One B-rep face of a CAD part: STEP entity #1352.
In plain terms, the planar face has unit normal (1, 0, 0).
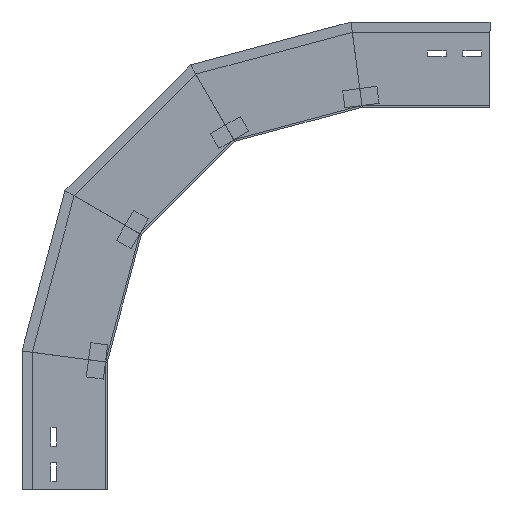
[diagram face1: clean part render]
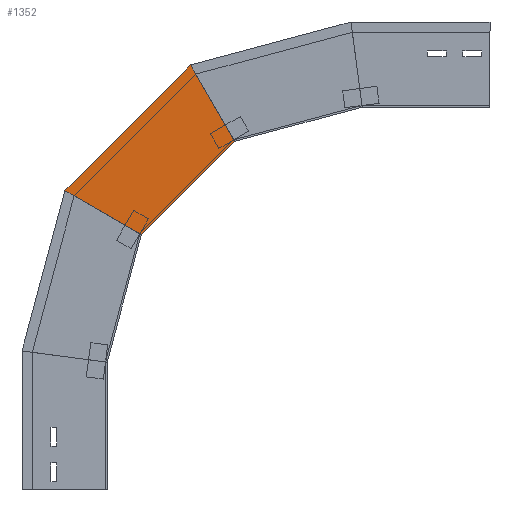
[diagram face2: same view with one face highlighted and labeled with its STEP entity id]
Its self-contained STEP definition (entity closure, numbers rounded to 3 decimals):
#122 = ORIENTED_EDGE ( 'NONE', *, *, #1836, .T. ) ;
#172 = LINE ( 'NONE', #312, #1805 ) ;
#262 = DIRECTION ( 'NONE',  ( 0., -0.866, -0.5 ) ) ;
#312 = CARTESIAN_POINT ( 'NONE',  ( 0., -173.604, 367.949 ) ) ;
#356 = EDGE_CURVE ( 'NONE', #1857, #867, #894, .T. ) ;
#415 = LINE ( 'NONE', #1006, #1048 ) ;
#470 = DIRECTION ( 'NONE',  ( 0., -0.5, -0.866 ) ) ;
#507 = CARTESIAN_POINT ( 'NONE',  ( 0., -149.719, 409.32 ) ) ;
#552 = DIRECTION ( 'NONE',  ( 0., 0., -1. ) ) ;
#631 = AXIS2_PLACEMENT_3D ( 'NONE', #1872, #1576, #552 ) ;
#642 = ORIENTED_EDGE ( 'NONE', *, *, #356, .F. ) ;
#690 = FACE_OUTER_BOUND ( 'NONE', #1213, .T. ) ;
#793 = DIRECTION ( 'NONE',  ( 0., -0.707, 0.707 ) ) ;
#848 = DIRECTION ( 'NONE',  ( 0., -0.707, 0.707 ) ) ;
#867 = VERTEX_POINT ( 'NONE', #507 ) ;
#894 = LINE ( 'NONE', #941, #1678 ) ;
#941 = CARTESIAN_POINT ( 'NONE',  ( 0., -19.205, 278.806 ) ) ;
#982 = VERTEX_POINT ( 'NONE', #1752 ) ;
#1006 = CARTESIAN_POINT ( 'NONE',  ( 0., 51.506, 349.517 ) ) ;
#1048 = VECTOR ( 'NONE', #848, 1000. ) ;
#1122 = CARTESIAN_POINT ( 'NONE',  ( 0., 49.541, 351.482 ) ) ;
#1167 = ORIENTED_EDGE ( 'NONE', *, *, #1611, .T. ) ;
#1172 = CARTESIAN_POINT ( 'NONE',  ( 0., -78.128, 277.773 ) ) ;
#1182 = LINE ( 'NONE', #1172, #1497 ) ;
#1213 = EDGE_LOOP ( 'NONE', ( #122, #1167, #642, #1679 ) ) ;
#1304 = CARTESIAN_POINT ( 'NONE',  ( 0., -40.117, 299.719 ) ) ;
#1352 = ADVANCED_FACE ( 'NONE', ( #690 ), #1880, .T. ) ;
#1421 = EDGE_CURVE ( 'NONE', #1726, #1857, #1182, .T. ) ;
#1497 = VECTOR ( 'NONE', #262, 1000. ) ;
#1576 = DIRECTION ( 'NONE',  ( 1., 0., 0. ) ) ;
#1611 = EDGE_CURVE ( 'NONE', #982, #867, #172, .T. ) ;
#1678 = VECTOR ( 'NONE', #793, 1000. ) ;
#1679 = ORIENTED_EDGE ( 'NONE', *, *, #1421, .F. ) ;
#1726 = VERTEX_POINT ( 'NONE', #1122 ) ;
#1752 = CARTESIAN_POINT ( 'NONE',  ( 0., -97.955, 498.978 ) ) ;
#1805 = VECTOR ( 'NONE', #470, 1000. ) ;
#1836 = EDGE_CURVE ( 'NONE', #1726, #982, #415, .T. ) ;
#1857 = VERTEX_POINT ( 'NONE', #1304 ) ;
#1872 = CARTESIAN_POINT ( 'NONE',  ( 0., -19.205, 278.806 ) ) ;
#1880 = PLANE ( 'NONE',  #631 ) ;
